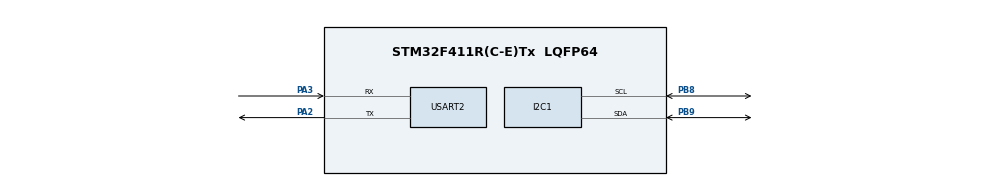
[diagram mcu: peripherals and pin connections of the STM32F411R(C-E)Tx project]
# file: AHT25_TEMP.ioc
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Mcu.Family=STM32F4
Mcu.Name=STM32F411R(C-E)Tx
Mcu.Package=LQFP64
NVIC.PriorityGroup=NVIC_PRIORITYGROUP_4
PA2.Mode=Asynchronous
PA2.Signal=USART2_TX
PA3.Mode=Asynchronous
PA3.Signal=USART2_RX
PB8.GPIO_Pu=GPIO_PULLUP
PB8.Mode=I2C
PB8.Signal=I2C1_SCL
PB9.GPIO_Pu=GPIO_PULLUP
PB9.Mode=I2C
PB9.Signal=I2C1_SDA
ProjectManager.HeapSize=0x200
ProjectManager.StackSize=0x400
ProjectManager.TargetToolchain=STM32CubeIDE
RCC.48MHZClocksFreq_Value=84000000
RCC.AHBFreq_Value=84000000
RCC.APB1CLKDivider=RCC_HCLK_DIV2
RCC.APB1Freq_Value=42000000
RCC.APB1TimFreq_Value=84000000
RCC.APB2Freq_Value=84000000
RCC.APB2TimFreq_Value=84000000
RCC.CortexFreq_Value=84000000
RCC.FLatency-AdvancedSettings=FLASH_LATENCY_2
RCC.HCLKFreq_Value=84000000
RCC.HSE_VALUE=8000000
RCC.HSI_VALUE=16000000
RCC.LSE_VALUE=32768
RCC.PLLN=336
RCC.PLLP=RCC_PLLP_DIV4
RCC.SYSCLKFreq_VALUE=84000000
RCC.SYSCLKSource=RCC_SYSCLKSOURCE_PLLCLK
RCC.VCOOutputFreq_Value=336000000
USART2.VirtualMode=VM_ASYNC
board=NUCLEO-F411RE

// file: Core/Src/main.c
/* USER CODE BEGIN Header */

/* USER CODE END Header */
#include "main.h"
#include "stdio.h"
#include "string.h"

I2C_HandleTypeDef hi2c1;

UART_HandleTypeDef huart2;

void SystemClock_Config(void);
static void MX_GPIO_Init(void);
static void MX_I2C1_Init(void);
static void MX_USART2_UART_Init(void);
/* USER CODE BEGIN PFP */
#define AHT25_ADDR 0x70 // Address of the AHT25 sensor

// AHT25 commands
#define AHT25_INIT_CMD 0xE1
#define AHT25_MEASURE_CMD 0xAC

/* USER CODE END PFP */

/* USER CODE BEGIN 0 */
float temperature, humidity;
char buffer[128];
void read_sensor_values(float *temperature, float *humidity)
{
    uint8_t data[6];
    uint8_t cmd = AHT25_MEASURE_CMD;

    HAL_I2C_Master_Transmit(&hi2c1, AHT25_ADDR,&cmd, 1, HAL_MAX_DELAY);
    HAL_Delay(100);
    HAL_I2C_Master_Receive(&hi2c1,0x71, data, 6, HAL_MAX_DELAY);

    *humidity = ((float)((data[1] << 12) | (data[2] << 4) | (data[3] >> 4))) / 1048576.0 * 100.0;
    *temperature = ((float)(((data[3] & 0x0F) << 16) | (data[4] << 8) | data[5])) / 1048576.0 * 200.0 - 50.0;
}

/* USER CODE END 0 */

int main(void)
{

  /* MCU Configuration--------------------------------------------------------*/

  /* Reset of all peripherals, Initializes the Flash interface and the Systick. */
  HAL_Init();

  /* Configure the system clock */
  SystemClock_Config();

  /* Initialize all configured peripherals */
  MX_GPIO_Init();
  MX_I2C1_Init();
  MX_USART2_UART_Init();

  /* Infinite loop */
  /* USER CODE BEGIN WHILE */
  while (1)
  {
//
//		if(HAL_I2C_IsDeviceReady(&hi2c1, 0x70,2,18)!=HAL_OK)
//	 	{
//	 		  HAL_GPIO_WritePin(GPIOA, GPIO_PIN_5, GPIO_PIN_SET);
//	 	}

	    // Initialize the AHT25 sensor

	    read_sensor_values(&temperature, &humidity);

	    // Print the sensor values over USART
	        char buffer[100];
	        sprintf(buffer, "Temperature: %.2f°C\r\nHumidity: %.2f%%\r\n", temperature, humidity);
	        HAL_UART_Transmit(&huart2, (uint8_t*)buffer, strlen(buffer), HAL_MAX_DELAY);

	        HAL_Delay(2000);

	}
    /* USER CODE END WHILE */

  }

void SystemClock_Config(void)
{
  RCC_OscInitTypeDef RCC_OscInitStruct = {0};
  RCC_ClkInitTypeDef RCC_ClkInitStruct = {0};

  /** Configure the main internal regulator output voltage
  */
  __HAL_RCC_PWR_CLK_ENABLE();
  __HAL_PWR_VOLTAGESCALING_CONFIG(PWR_REGULATOR_VOLTAGE_SCALE1);

  /** Initializes the RCC Oscillators according to the specified parameters
  * in the RCC_OscInitTypeDef structure.
  */
  RCC_OscInitStruct.OscillatorType = RCC_OSCILLATORTYPE_HSI;
  RCC_OscInitStruct.HSIState = RCC_HSI_ON;
  RCC_OscInitStruct.HSICalibrationValue = RCC_HSICALIBRATION_DEFAULT;
  RCC_OscInitStruct.PLL.PLLState = RCC_PLL_NONE;
  if (HAL_RCC_OscConfig(&RCC_OscInitStruct) != HAL_OK)
  {
    Error_Handler();
  }

  /** Initializes the CPU, AHB and APB buses clocks
  */
  RCC_ClkInitStruct.ClockType = RCC_CLOCKTYPE_HCLK|RCC_CLOCKTYPE_SYSCLK
                              |RCC_CLOCKTYPE_PCLK1|RCC_CLOCKTYPE_PCLK2;
  RCC_ClkInitStruct.SYSCLKSource = RCC_SYSCLKSOURCE_HSI;
  RCC_ClkInitStruct.AHBCLKDivider = RCC_SYSCLK_DIV1;
  RCC_ClkInitStruct.APB1CLKDivider = RCC_HCLK_DIV1;
  RCC_ClkInitStruct.APB2CLKDivider = RCC_HCLK_DIV1;

  if (HAL_RCC_ClockConfig(&RCC_ClkInitStruct, FLASH_LATENCY_0) != HAL_OK)
  {
    Error_Handler();
  }
}

static void MX_I2C1_Init(void)
{

  hi2c1.Instance = I2C1;
  hi2c1.Init.ClockSpeed = 100000;
  hi2c1.Init.DutyCycle = I2C_DUTYCYCLE_2;
  hi2c1.Init.OwnAddress1 = 0;
  hi2c1.Init.AddressingMode = I2C_ADDRESSINGMODE_7BIT;
  hi2c1.Init.DualAddressMode = I2C_DUALADDRESS_DISABLE;
  hi2c1.Init.OwnAddress2 = 0;
  hi2c1.Init.GeneralCallMode = I2C_GENERALCALL_DISABLE;
  hi2c1.Init.NoStretchMode = I2C_NOSTRETCH_DISABLE;
  if (HAL_I2C_Init(&hi2c1) != HAL_OK)
  {
    Error_Handler();
  }

}

static void MX_USART2_UART_Init(void)
{

  huart2.Instance = USART2;
  huart2.Init.BaudRate = 115200;
  huart2.Init.WordLength = UART_WORDLENGTH_8B;
  huart2.Init.StopBits = UART_STOPBITS_1;
  huart2.Init.Parity = UART_PARITY_NONE;
  huart2.Init.Mode = UART_MODE_TX_RX;
  huart2.Init.HwFlowCtl = UART_HWCONTROL_NONE;
  huart2.Init.OverSampling = UART_OVERSAMPLING_16;
  if (HAL_UART_Init(&huart2) != HAL_OK)
  {
    Error_Handler();
  }

}

static void MX_GPIO_Init(void)
{

  /* GPIO Ports Clock Enable */
  __HAL_RCC_GPIOA_CLK_ENABLE();
  __HAL_RCC_GPIOB_CLK_ENABLE();

}

void Error_Handler(void)
{
  __disable_irq();
  while (1)
  {
  }
}
